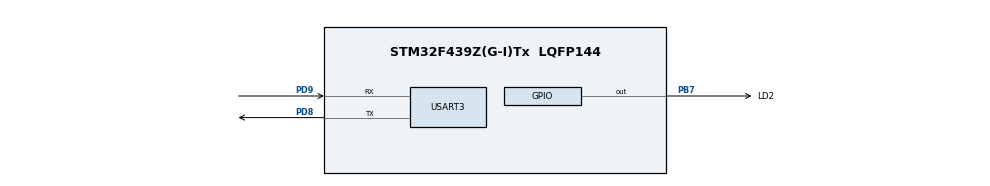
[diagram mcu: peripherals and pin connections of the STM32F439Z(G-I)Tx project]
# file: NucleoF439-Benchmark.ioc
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HASH.SecureHashAlgorithmType=SHA256
HASH.pKey=__NULL
Mcu.Family=STM32F4
Mcu.Name=STM32F439Z(G-I)Tx
Mcu.Package=LQFP144
NVIC.PriorityGroup=NVIC_PRIORITYGROUP_4
PB7.GPIO_Label=LD2
PB7.Signal=GPIO_Output
PD8.Mode=Asynchronous
PD8.Signal=USART3_TX
PD9.Mode=Asynchronous
PD9.Signal=USART3_RX
ProjectManager.HeapSize=0x200
ProjectManager.StackSize=0x400
ProjectManager.TargetToolchain=STM32CubeIDE
RCC.48MHZClocksFreq_Value=48000000
RCC.AHBFreq_Value=168000000
RCC.APB1CLKDivider=RCC_HCLK_DIV4
RCC.APB1Freq_Value=42000000
RCC.APB1TimFreq_Value=84000000
RCC.APB2CLKDivider=RCC_HCLK_DIV2
RCC.APB2Freq_Value=84000000
RCC.APB2TimFreq_Value=168000000
RCC.CortexFreq_Value=168000000
RCC.HCLKFreq_Value=168000000
RCC.HSE_VALUE=25000000
RCC.HSI_VALUE=16000000
RCC.LSE_VALUE=32768
RCC.PLLM=8
RCC.PLLN=168
RCC.PLLQ=7
RCC.SYSCLKFreq_VALUE=168000000
RCC.SYSCLKSource=RCC_SYSCLKSOURCE_PLLCLK
RCC.VCOOutputFreq_Value=336000000
USART3.VirtualMode=VM_ASYNC
VP_CRC_VS_CRC.Mode=CRC_Activate
VP_CRYP_VS_CRYP.Mode=CRYP_Activate
VP_HASH_VS_HASH.Mode=HASH_Activate
VP_RNG_VS_RNG.Mode=RNG_Activate
VP_wolfSSL.I-CUBE-wolfSSL_VS_wolfSSLJjwolfSSL_5.8.2_5.8.2.Mode=wolfSSLJjwolfSSL
board=custom
wolfSSL.I-CUBE-wolfSSL.5.8.2.WOLF_CONF_AESGCM=0
wolfSSL.I-CUBE-wolfSSL.5.8.2.WOLF_CONF_ARMASM=1
wolfSSL.I-CUBE-wolfSSL.5.8.2.WOLF_CONF_CHAPOLY=0
wolfSSL.I-CUBE-wolfSSL.5.8.2.WOLF_CONF_DH=0
wolfSSL.I-CUBE-wolfSSL.5.8.2.WOLF_CONF_TEST=0
wolfSSL.I-CUBE-wolfSSL.5.8.2.WOLF_CONF_TLS12=0
wolfSSL.I-CUBE-wolfSSL.5.8.2.WOLF_CONF_TLS13=0
wolfSSL.I-CUBE-wolfSSL.5.8.2.WOLF_CONF_WOLFCRYPT_ONLY=1
wolfSSL.I-CUBE-wolfSSL.5.8.2.wolfSSLCcwolfSSLJjwolfCryptJjCore=true

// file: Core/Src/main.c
/* USER CODE BEGIN Header */
/**
  ******************************************************************************
  * @file           : main.c
  * @brief          : Main program body
  ******************************************************************************
  * @attention
  *
  * Copyright (c) 2026 STMicroelectronics.
  * All rights reserved.
  *
  * This software is licensed under terms that can be found in the LICENSE file
  * in the root directory of this software component.
  * If no LICENSE file comes with this software, it is provided AS-IS.
  *
  ******************************************************************************
  */
/* USER CODE END Header */
#include "main.h"

/* USER CODE BEGIN Includes */

#include <stdio.h>
#include "ecss_packet.h"
#include "input.h"
#include "benchmark.h"

/* USER CODE END Includes */

CRC_HandleTypeDef hcrc;

CRYP_HandleTypeDef hcryp;
__ALIGN_BEGIN static const uint32_t pKeyCRYP[6] __ALIGN_END = {
                            0x00000000,0x00000000,0x00000000,0x00000000,0x00000000,0x00000000};

HASH_HandleTypeDef hhash;

RNG_HandleTypeDef hrng;

UART_HandleTypeDef huart3;

void SystemClock_Config(void);
static void MX_GPIO_Init(void);
static void MX_USART3_UART_Init(void);
static void MX_CRYP_Init(void);
static void MX_HASH_Init(void);
static void MX_RNG_Init(void);
static void MX_CRC_Init(void);

/* USER CODE BEGIN 0 */

int _write(int fd, char *ptr, int len)
{
    if (fd == 1 || fd == 2)
    {
        // Send debug output as ECSS DEBUG_LOG packet
        if (sendDebugPacket(&huart3, ptr, len) == 0)
            return len;
        else
            return -1;
    }
    return -1;
}

/* USER CODE END 0 */

int main(void)
{

  /* MCU Configuration--------------------------------------------------------*/

  /* Reset of all peripherals, Initializes the Flash interface and the Systick. */
  HAL_Init();

  /* Configure the system clock */
  SystemClock_Config();

  /* Initialize all configured peripherals */
  MX_GPIO_Init();
  MX_USART3_UART_Init();
  MX_CRYP_Init();
  MX_HASH_Init();
  MX_RNG_Init();
  MX_CRC_Init();
  /* USER CODE BEGIN 2 */

    printf("Digital Signature Benchmark — NucleoF439\r\n");
    benchmarkRun();

  /* USER CODE END 2 */

  /* Infinite loop */
  while (1)
  {

  }
}

void SystemClock_Config(void)
{
  RCC_OscInitTypeDef RCC_OscInitStruct = {0};
  RCC_ClkInitTypeDef RCC_ClkInitStruct = {0};

  /** Configure the main internal regulator output voltage
  */
  __HAL_RCC_PWR_CLK_ENABLE();
  __HAL_PWR_VOLTAGESCALING_CONFIG(PWR_REGULATOR_VOLTAGE_SCALE3);

  /** Initializes the RCC Oscillators according to the specified parameters
  * in the RCC_OscInitTypeDef structure.
  */
  RCC_OscInitStruct.OscillatorType = RCC_OSCILLATORTYPE_HSI;
  RCC_OscInitStruct.HSIState = RCC_HSI_ON;
  RCC_OscInitStruct.HSICalibrationValue = RCC_HSICALIBRATION_DEFAULT;
  RCC_OscInitStruct.PLL.PLLState = RCC_PLL_ON;
  RCC_OscInitStruct.PLL.PLLSource = RCC_PLLSOURCE_HSI;
  RCC_OscInitStruct.PLL.PLLM = 16;
  RCC_OscInitStruct.PLL.PLLN = 192;
  RCC_OscInitStruct.PLL.PLLP = RCC_PLLP_DIV2;
  RCC_OscInitStruct.PLL.PLLQ = 4;
  if (HAL_RCC_OscConfig(&RCC_OscInitStruct) != HAL_OK)
  {
    Error_Handler();
  }

  /** Initializes the CPU, AHB and APB buses clocks
  */
  RCC_ClkInitStruct.ClockType = RCC_CLOCKTYPE_HCLK|RCC_CLOCKTYPE_SYSCLK
                              |RCC_CLOCKTYPE_PCLK1|RCC_CLOCKTYPE_PCLK2;
  RCC_ClkInitStruct.SYSCLKSource = RCC_SYSCLKSOURCE_HSI;
  RCC_ClkInitStruct.AHBCLKDivider = RCC_SYSCLK_DIV1;
  RCC_ClkInitStruct.APB1CLKDivider = RCC_HCLK_DIV1;
  RCC_ClkInitStruct.APB2CLKDivider = RCC_HCLK_DIV1;

  if (HAL_RCC_ClockConfig(&RCC_ClkInitStruct, FLASH_LATENCY_0) != HAL_OK)
  {
    Error_Handler();
  }
}

static void MX_CRC_Init(void)
{

  hcrc.Instance = CRC;
  if (HAL_CRC_Init(&hcrc) != HAL_OK)
  {
    Error_Handler();
  }

}

static void MX_CRYP_Init(void)
{

  hcryp.Instance = CRYP;
  hcryp.Init.DataType = CRYP_DATATYPE_32B;
  hcryp.Init.pKey = (uint32_t *)pKeyCRYP;
  hcryp.Init.Algorithm = CRYP_TDES_ECB;
  hcryp.Init.DataWidthUnit = CRYP_DATAWIDTHUNIT_WORD;
  if (HAL_CRYP_Init(&hcryp) != HAL_OK)
  {
    Error_Handler();
  }

}

static void MX_HASH_Init(void)
{

  hhash.Init.DataType = HASH_DATATYPE_32B;
  if (HAL_HASH_Init(&hhash) != HAL_OK)
  {
    Error_Handler();
  }

}

static void MX_RNG_Init(void)
{

  hrng.Instance = RNG;
  if (HAL_RNG_Init(&hrng) != HAL_OK)
  {
    Error_Handler();
  }

}

static void MX_USART3_UART_Init(void)
{

  huart3.Instance = USART3;
  huart3.Init.BaudRate = 115200;
  huart3.Init.WordLength = UART_WORDLENGTH_8B;
  huart3.Init.StopBits = UART_STOPBITS_1;
  huart3.Init.Parity = UART_PARITY_NONE;
  huart3.Init.Mode = UART_MODE_TX_RX;
  huart3.Init.HwFlowCtl = UART_HWCONTROL_NONE;
  huart3.Init.OverSampling = UART_OVERSAMPLING_16;
  if (HAL_UART_Init(&huart3) != HAL_OK)
  {
    Error_Handler();
  }

}

static void MX_GPIO_Init(void)
{
  GPIO_InitTypeDef GPIO_InitStruct = {0};

  /* GPIO Ports Clock Enable */
  __HAL_RCC_GPIOD_CLK_ENABLE();
  __HAL_RCC_GPIOB_CLK_ENABLE();

  /*Configure GPIO pin Output Level */
  HAL_GPIO_WritePin(LD2_GPIO_Port, LD2_Pin, GPIO_PIN_RESET);

  /*Configure GPIO pin : LD2_Pin */
  GPIO_InitStruct.Pin = LD2_Pin;
  GPIO_InitStruct.Mode = GPIO_MODE_OUTPUT_PP;
  GPIO_InitStruct.Pull = GPIO_NOPULL;
  GPIO_InitStruct.Speed = GPIO_SPEED_FREQ_LOW;
  HAL_GPIO_Init(LD2_GPIO_Port, &GPIO_InitStruct);

}

void Error_Handler(void)
{
  __disable_irq();
  while (1)
  {
  }
}
